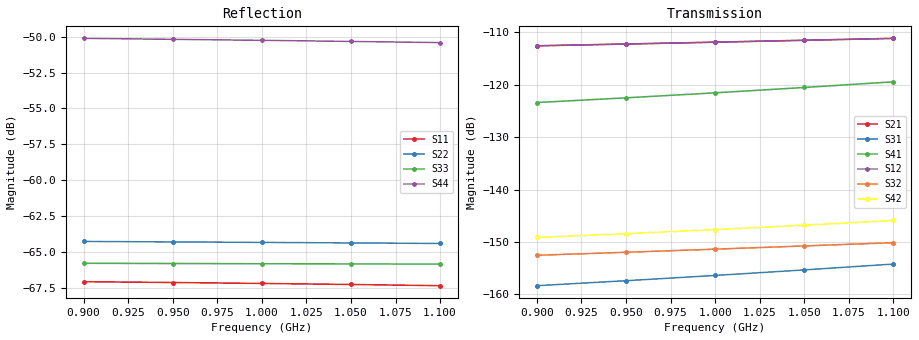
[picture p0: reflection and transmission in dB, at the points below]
! Touchstone file from project test_multiport
! Exported from HFSS 2019.2.0
!Data is not renormalized
# GHZ S MA
! Modal data exported
! Port[1] = 1:1
! Port[2] = 2:1
! Port[3] = 3:1
! Port[4] = 4:1
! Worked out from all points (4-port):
!   5 points, 900 MHz to 1.1 GHz, reference per port
!   strongest paths, dB at 900 MHz, 950 MHz, 1 GHz, 1.05 GHz, 1.1 GHz:
!     S21: -112.6, -112.2, -111.9, -111.5, -111.2
!     S41: -123.4, -122.5, -121.6, -120.5, -119.5
!     S42: -149.1, -148.4, -147.6, -146.8, -145.9
!     S32: -152.5, -152.0, -151.4, -150.8, -150.1
!     S31: -158.3, -157.4, -156.4, -155.3, -154.2
!     S43: -163.7, -162.6, -161.5, -160.3, -159.1
!   lowest |S11| = -67.4 dB at 1.1 GHz (marker M1), VSWR 1.00
!   |S11| at or under -10 dB: start of sweep to end of sweep
0.9  0.0004426 -180.0  2.348e-06 -180.0  1.21e-08 180.0  6.754e-07 180.0
     2.348e-06 -180.0  0.0006113 180.0  2.36e-08 180.0  3.49e-08 -180.0
     1.21e-08 180.0  2.36e-08 -180.0  0.000513 -180.0  6.546e-09 -0.0
     6.754e-07 180.0  3.49e-08 -180.0  6.546e-09 -0.0  0.003119 -180.0
0.95  0.0004397 180.0  2.442e-06 -180.0  1.35e-08 -180.0  7.489e-07 -180.0
      2.442e-06 180.0  0.000609 180.0  2.52e-08 180.0  3.792e-08 -180.0
      1.35e-08 180.0  2.52e-08 180.0  0.0005121 180.0  7.382e-09 0.0
      7.489e-07 -180.0  3.792e-08 -180.0  7.382e-09 0.0  0.003095 180.0
1  0.0004364 -180.0  2.543e-06 -180.0  1.515e-08 -180.0  8.361e-07 -180.0
   2.543e-06 -180.0  0.0006066 -180.0  2.699e-08 -180.0  4.147e-08 -180.0
   1.515e-08 -180.0  2.699e-08 -180.0  0.0005112 -180.0  8.392e-09 0.0
   8.361e-07 -180.0  4.147e-08 -180.0  8.392e-09 0.0  0.00307 -180.0
1.05  0.0004328 -180.0  2.651e-06 -180.0  1.711e-08 180.0  9.402e-07 180.0
      2.651e-06 -180.0  0.0006041 180.0  2.896e-08 -180.0  4.568e-08 180.0
      1.711e-08 180.0  2.896e-08 -180.0  0.0005104 -180.0  9.622e-09 -0.0
      9.402e-07 180.0  4.568e-08 -180.0  9.622e-09 -0.0  0.003043 -180.0
1.1  0.0004286 180.0  2.765e-06 -180.0  1.946e-08 -180.0  1.065e-06 -180.0
     2.765e-06 -180.0  0.0006014 180.0  3.114e-08 180.0  5.069e-08 180.0
     1.946e-08 -180.0  3.114e-08 180.0  0.0005097 -180.0  1.113e-08 0.0
     1.065e-06 -180.0  5.069e-08 180.0  1.113e-08 0.0  0.003015 180.0
